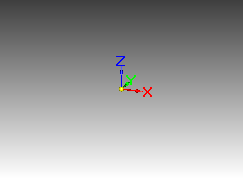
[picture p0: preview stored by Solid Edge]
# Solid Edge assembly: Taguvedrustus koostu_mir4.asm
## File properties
Author: Türk
Template: Iso Assembly.asm
Last saved by: Türk
Revision: 2
Application: Solid Edge
Username: Türk
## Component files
Poldikoostu6_mir.asm
Hoidja.tagu.par
Poldikoostu6_mir1.asm
Poldikoostu8_mir.asm
si.par
